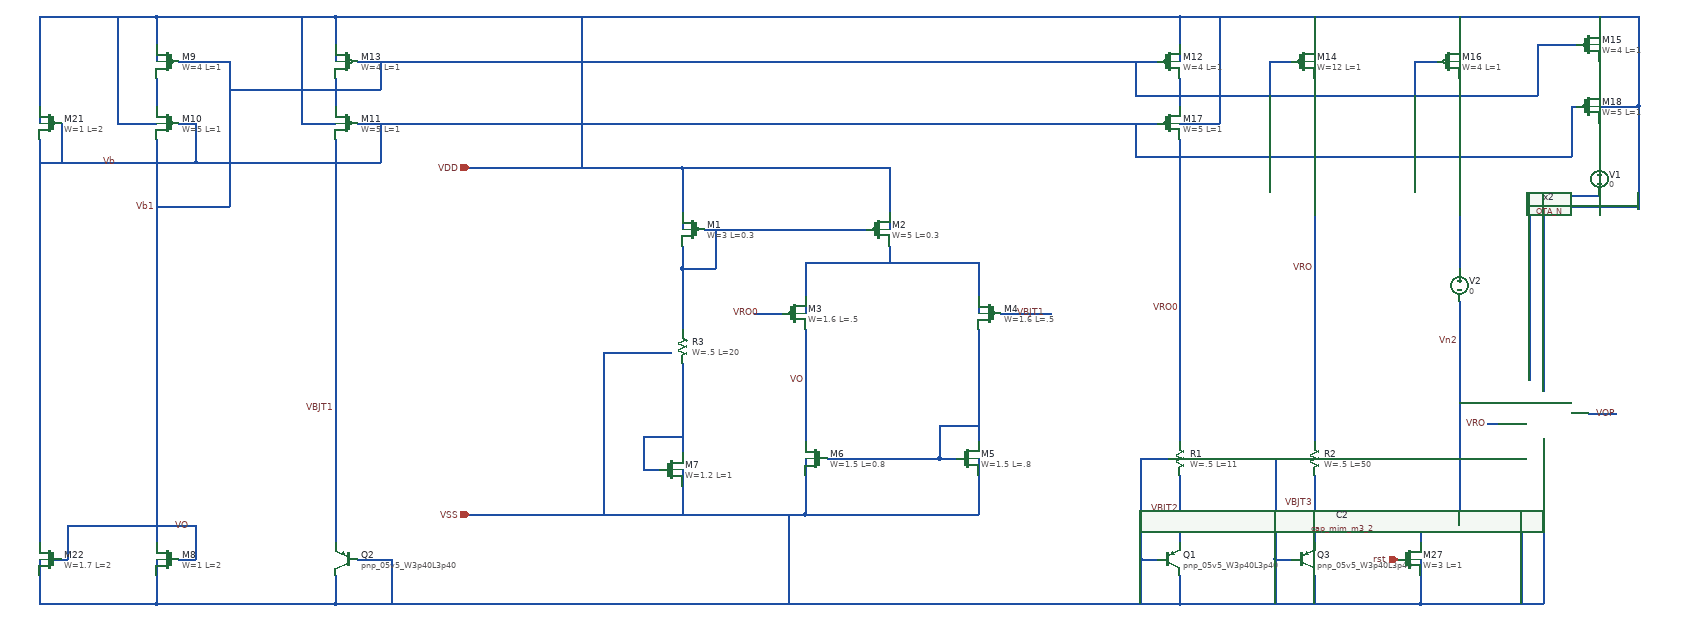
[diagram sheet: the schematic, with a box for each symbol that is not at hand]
v {xschem version=3.4.4 file_version=1.2
}
G {}
K {}
V {}
S {}
E {}
N 2615 -717.5 2615 -597.5 {
lab=VBJT2}
N 1145 -1457.5 2575 -1457.5 {
lab=Vb1}
N 1105 -1537.5 1105 -1487.5 {
lab=VDD}
N 1105 -1537.5 2615 -1537.5 {
lab=VDD}
N 2615 -1537.5 2615 -1487.5 {
lab=VDD}
N 2615 -1487.5 2615 -1457.5 {
lab=VDD}
N 1105 -1487.5 1105 -1457.5 {
lab=VDD}
N 1105 -537.5 1105 -487.5 {
lab=VSS}
N 1105 -487.5 2615 -487.5 {
lab=VSS}
N 2615 -537.5 2615 -487.5 {
lab=VSS}
N 2545 -567.5 2575 -567.5 {
lab=VSS}
N 2545 -567.5 2545 -487.5 {
lab=VSS}
N 1145 -567.5 1175 -567.5 {
lab=VSS}
N 2855 -717.5 2855 -597.5 {
lab=VBJT3}
N 2785 -567.5 2815 -567.5 {
lab=VSS}
N 2615 -1537.5 2955 -1537.5 {
lab=VDD}
N 2855 -1487.5 2855 -1457.5 {
lab=VDD}
N 2855 -1327.5 2855 -797.5 {
lab=VRO}
N 2855 -797.5 2855 -777.5 {
lab=VRO}
N 2615 -487.5 2955 -487.5 {
lab=VSS}
N 2855 -537.5 2855 -487.5 {
lab=VSS}
N 2785 -567.5 2785 -487.5 {
lab=VSS}
N 2955 -1537.5 3225 -1537.5 {
lab=VDD}
N 3115 -1517.5 3115 -1487.5 {
lab=VDD}
N 3115 -1537.5 3115 -1517.5 {
lab=VDD}
N 1945 -1097.5 1945 -1037.5 {
lab=#net1}
N 1945 -1097.5 2255 -1097.5 {
lab=#net1}
N 2255 -1097.5 2255 -1037.5 {
lab=#net1}
N 2255 -977.5 2255 -777.5 {
lab=#net2}
N 1945 -977.5 1945 -777.5 {
lab=VO}
N 1985 -747.5 2015 -747.5 {
lab=#net2}
N 2185 -747.5 2215 -747.5 {
lab=#net2}
N 2185 -807.5 2185 -747.5 {
lab=#net2}
N 2185 -807.5 2255 -807.5 {
lab=#net2}
N 1945 -717.5 1945 -647.5 {
lab=VSS}
N 1945 -647.5 2255 -647.5 {
lab=VSS}
N 2255 -717.5 2255 -647.5 {
lab=VSS}
N 1945 -747.5 1945 -717.5 {
lab=VSS}
N 2255 -747.5 2255 -717.5 {
lab=VSS}
N 2255 -1037.5 2255 -1007.5 {
lab=#net1}
N 1945 -1037.5 1945 -1007.5 {
lab=#net1}
N 2095 -1187.5 2095 -1157.5 {
lab=VDD}
N 2095 -1127.5 2095 -1097.5 {
lab=#net1}
N 1725 -1187.5 1725 -1157.5 {
lab=VDD}
N 1725 -1127.5 1725 -1087.5 {
lab=#net3}
N 1725 -1087.5 1785 -1087.5 {
lab=#net3}
N 1785 -1157.5 1785 -1087.5 {
lab=#net3}
N 1765 -1157.5 2055 -1157.5 {
lab=#net3}
N 1545 -647.5 1945 -647.5 {
lab=VSS}
N 1725 -1267.5 2095 -1267.5 {
lab=VDD}
N 1345 -647.5 1545 -647.5 {
lab=VSS}
N 1725 -1087.5 1725 -1027.5 {
lab=#net3}
N 1725 -1027.5 1725 -1017.5 {
lab=#net3}
N 1545 -1537.5 1545 -1367.5 {
lab=VDD}
N 1915 -647.5 1915 -487.5 {
lab=VSS}
N 2015 -747.5 2185 -747.5 {
lab=#net2}
N 1655 -727.5 1685 -727.5 {
lab=#net4}
N 1655 -787.5 1655 -727.5 {
lab=#net4}
N 1655 -787.5 1725 -787.5 {
lab=#net4}
N 1725 -727.5 1725 -697.5 {
lab=VSS}
N 1725 -917.5 1725 -757.5 {
lab=#net4}
N 1725 -697.5 1725 -647.5 {
lab=VSS}
N 1725 -1017.5 1725 -977.5 {
lab=#net3}
N 2295 -1007.5 2385 -1007.5 {
lab=VBJT1}
N 1855 -1007.5 1905 -1007.5 {
lab=VRO0}
N 825 -567.5 855 -567.5 {
lab=VO}
N 855 -627.5 855 -567.5 {
lab=VO}
N 785 -567.5 785 -537.5 {
lab=VSS}
N 785 -537.5 785 -487.5 {
lab=VSS}
N 785 -487.5 1105 -487.5 {
lab=VSS}
N 785 -1537.5 785 -1487.5 {
lab=VDD}
N 785 -1487.5 785 -1457.5 {
lab=VDD}
N 785 -1427.5 785 -1377.5 {
lab=#net5}
N 1345 -1267.5 1725 -1267.5 {
lab=VDD}
N 1545 -1367.5 1545 -1267.5 {
lab=VDD}
N 855 -1347.5 855 -1277.5 {
lab=Vb}
N 825 -1347.5 855 -1347.5 {
lab=Vb}
N 825 -1457.5 855 -1457.5 {
lab=Vb1}
N 785 -1537.5 1105 -1537.5 {
lab=VDD}
N 1105 -1427.5 1105 -1377.5 {
lab=#net6}
N 2615 -1427.5 2615 -1377.5 {
lab=#net7}
N 2855 -1437.5 2855 -1387.5 {
lab=VRO}
N 2855 -1537.5 2855 -1487.5 {
lab=VDD}
N 2535 -1457.5 2535 -1397.5 {
lab=Vb1}
N 2535 -1397.5 2875 -1397.5 {
lab=Vb1}
N 2775 -1457.5 2775 -1397.5 {
lab=Vb1}
N 2775 -1457.5 2815 -1457.5 {
lab=Vb1}
N 1145 -1347.5 2575 -1347.5 {
lab=Vb}
N 2615 -1317.5 2615 -777.5 {
lab=VRO0}
N 1185 -1457.5 1185 -1407.5 {
lab=Vb1}
N 1185 -1347.5 1185 -1277.5 {
lab=Vb}
N 855 -1457.5 915 -1457.5 {
lab=Vb1}
N 915 -1457.5 915 -1197.5 {
lab=Vb1}
N 785 -1197.5 915 -1197.5 {
lab=Vb1}
N 2875 -1397.5 3145 -1397.5 {
lab=Vb1}
N 785 -1317.5 785 -1147.5 {
lab=Vb1}
N 785 -1097.5 785 -597.5 {
lab=Vb1}
N 1175 -567.5 1205 -567.5 {
lab=VSS}
N 1205 -507.5 1205 -487.5 {
lab=VSS}
N 1205 -567.5 1205 -517.5 {
lab=VSS}
N 1205 -517.5 1205 -507.5 {
lab=VSS}
N 1105 -677.5 1105 -597.5 {
lab=VBJT1}
N 1105 -837.5 1105 -737.5 {
lab=VBJT1}
N 1105 -1317.5 1105 -837.5 {
lab=VBJT1}
N 1105 -737.5 1105 -677.5 {
lab=VBJT1}
N 915 -1407.5 1185 -1407.5 {
lab=Vb1}
N 1725 -1267.5 1725 -1187.5 {
lab=VDD}
N 2095 -1267.5 2095 -1187.5 {
lab=VDD}
N 785 -1147.5 785 -1097.5 {
lab=Vb1}
N 575 -1377.5 575 -1347.5 {
lab=VDD}
N 575 -1277.5 855 -1277.5 {
lab=Vb}
N 575 -1537.5 575 -1377.5 {
lab=VDD}
N 575 -1537.5 785 -1537.5 {
lab=VDD}
N 625 -627.5 855 -627.5 {
lab=VO}
N 625 -627.5 625 -567.5 {
lab=VO}
N 595 -567.5 625 -567.5 {
lab=VO}
N 575 -1317.5 575 -627.5 {
lab=Vb}
N 615 -1347.5 615 -1277.5 {
lab=Vb}
N 855 -1277.5 1185 -1277.5 {
lab=Vb}
N 2855 -1387.5 2855 -1327.5 {
lab=VRO}
N 2795 -747.5 2835 -747.5 {
lab=VSS}
N 2785 -747.5 2785 -567.5 {
lab=VSS}
N 2785 -747.5 2795 -747.5 {
lab=VSS}
N 2545 -747.5 2545 -567.5 {
lab=VSS}
N 2545 -747.5 2595 -747.5 {
lab=VSS}
N 1585 -937.5 1705 -937.5 {
lab=VSS}
N 1585 -937.5 1585 -647.5 {
lab=VSS}
N 3365 -1517.5 3365 -1487.5 {
lab=VDD}
N 3365 -1457.5 3365 -1407.5 {
lab=#net8}
N 3255 -1487.5 3255 -1397.5 {
lab=Vb1}
N 3255 -1487.5 3325 -1487.5 {
lab=Vb1}
N 2535 -1347.5 2535 -1287.5 {
lab=Vb}
N 3315 -1377.5 3315 -1287.5 {
lab=Vb}
N 3315 -1377.5 3325 -1377.5 {
lab=Vb}
N 3365 -1537.5 3365 -1517.5 {
lab=VDD}
N 3365 -1347.5 3365 -1277.5 {
lab=#net9}
N 715 -1347.5 785 -1347.5 {
lab=VDD}
N 715 -1537.5 715 -1347.5 {
lab=VDD}
N 1045 -1347.5 1105 -1347.5 {
lab=VDD}
N 1045 -1537.5 1045 -1347.5 {
lab=VDD}
N 2615 -1347.5 2685 -1347.5 {
lab=VDD}
N 2685 -1537.5 2685 -1347.5 {
lab=VDD}
N 3365 -1377.5 3435 -1377.5 {
lab=VDD}
N 3435 -1537.5 3435 -1377.5 {
lab=VDD}
N 3165 -627.5 3225 -627.5 {
lab=VSS}
N 3045 -627.5 3045 -597.5 {
lab=VSS}
N 3045 -567.5 3045 -537.5 {
lab=VSS}
N 3115 -1387.5 3115 -1377.5 {
lab=#net10}
N 3115 -1317.5 3115 -1227.5 {
lab=#net10}
N 3115 -1377.5 3115 -1317.5 {
lab=#net10}
N 3045 -627.5 3085 -627.5 {
lab=VSS}
N 3225 -627.5 3225 -487.5 {
lab=VSS}
N 3125 -627.5 3155 -627.5 {
lab=VSS}
N 575 -627.5 575 -597.5 {
lab=Vb}
N 575 -537.5 575 -487.5 {
lab=VSS}
N 575 -567.5 575 -537.5 {
lab=VSS}
N 575 -487.5 785 -487.5 {
lab=VSS}
N 3115 -1427.5 3115 -1387.5 {
lab=#net10}
N 3035 -1457.5 3075 -1457.5 {
lab=Vb1}
N 3035 -1457.5 3035 -1397.5 {
lab=Vb1}
N 3075 -487.5 3155 -487.5 {
lab=VSS}
N 3115 -1227.5 3115 -1087.5 {
lab=#net10}
N 3115 -1027.5 3115 -807.5 {
lab=VSS}
N 2955 -487.5 3045 -487.5 {
lab=VSS}
N 3045 -487.5 3075 -487.5 {
lab=VSS}
N 3155 -627.5 3165 -627.5 {
lab=VSS}
N 2535 -1287.5 3315 -1287.5 {
lab=Vb}
N 3145 -1397.5 3255 -1397.5 {
lab=Vb1}
N 3225 -1537.5 3435 -1537.5 {
lab=VDD}
N 3085 -627.5 3125 -627.5 {
lab=VSS}
N 3155 -487.5 3195 -487.5 {
lab=VSS}
N 3045 -537.5 3045 -487.5 {
lab=VSS}
N 3265 -1057.5 3265 -877.5 {
lab=VDD}
N 3265 -777.5 3265 -487.5 {
lab=VSS}
N 3215 -487.5 3265 -487.5 {
lab=VSS}
N 3195 -487.5 3215 -487.5 {
lab=VSS}
N 3345 -827.5 3395 -827.5 {
lab=VOP}
N 3265 -782.5 3265 -777.5 {
lab=VSS}
N 3115 -807.5 3115 -627.5 {
lab=VSS}
N 3265 -877.5 3265 -867.5 {
lab=VDD}
N 3240 -1217.5 3240 -887.5 {
lab=#net11}
N 3240 -1217.5 3365 -1217.5 {
lab=#net11}
N 3265 -1197.5 3265 -1057.5 {
lab=VDD}
N 3265 -1197.5 3435 -1197.5 {
lab=VDD}
N 3435 -1377.5 3435 -1192.5 {
lab=VDD}
N 3115 -847.5 3185 -847.5 {
lab=VSS}
N 3165 -810 3185 -810 {
lab=#net12}
C {sky130_fd_pr/pnp_05v5.sym} 2595 -567.5 0 0 {name=Q1
model=pnp_05v5_W3p40L3p40
m=6
spiceprefix=X
}
C {sky130_fd_pr/pnp_05v5.sym} 1125 -567.5 0 1 {name=Q2
model=pnp_05v5_W3p40L3p40
m=1
spiceprefix=X
}
C {sky130_fd_pr/pfet_01v8.sym} 2595 -1457.5 0 0 {name=M12
L=1
W=4
nf=2
mult=1
ad="'int((nf+1)/2) * W/nf * 0.29'" 
pd="'2*int((nf+1)/2) * (W/nf + 0.29)'"
as="'int((nf+2)/2) * W/nf * 0.29'" 
ps="'2*int((nf+2)/2) * (W/nf + 0.29)'"
nrd="'0.29 / W'" nrs="'0.29 / W'"
sa=0 sb=0 sd=0
model=pfet_01v8
spiceprefix=X
}
C {sky130_fd_pr/pfet_01v8.sym} 1125 -1457.5 0 1 {name=M13
L=1
W=4
nf=2
mult=1
ad="'int((nf+1)/2) * W/nf * 0.29'" 
pd="'2*int((nf+1)/2) * (W/nf + 0.29)'"
as="'int((nf+2)/2) * W/nf * 0.29'" 
ps="'2*int((nf+2)/2) * (W/nf + 0.29)'"
nrd="'0.29 / W'" nrs="'0.29 / W'"
sa=0 sb=0 sd=0
model=pfet_01v8
spiceprefix=X
}
C {sky130_fd_pr/pfet_01v8.sym} 2835 -1457.5 0 0 {name=M14
L=1
W=12
nf=2
mult=1
ad="'int((nf+1)/2) * W/nf * 0.29'" 
pd="'2*int((nf+1)/2) * (W/nf + 0.29)'"
as="'int((nf+2)/2) * W/nf * 0.29'" 
ps="'2*int((nf+2)/2) * (W/nf + 0.29)'"
nrd="'0.29 / W'" nrs="'0.29 / W'"
sa=0 sb=0 sd=0
model=pfet_01v8
spiceprefix=X
}
C {sky130_fd_pr/pnp_05v5.sym} 2835 -567.5 0 0 {name=Q3
model=pnp_05v5_W3p40L3p40
m=1
spiceprefix=X
}
C {devices/lab_wire.sym} 2855 -1087.5 0 0 {name=p6 sig_type=std_logic lab=VRO}
C {devices/lab_wire.sym} 2615 -657.5 0 0 {name=p7 sig_type=std_logic lab=VBJT2}
C {devices/lab_wire.sym} 2855 -667.5 0 0 {name=p8 sig_type=std_logic lab=VBJT3}
C {sky130_fd_pr/pfet_01v8.sym} 3095 -1457.5 0 0 {name=M16
L=1
W=4
nf=2
mult=1
ad="'int((nf+1)/2) * W/nf * 0.29'" 
pd="'2*int((nf+1)/2) * (W/nf + 0.29)'"
as="'int((nf+2)/2) * W/nf * 0.29'" 
ps="'2*int((nf+2)/2) * (W/nf + 0.29)'"
nrd="'0.29 / W'" nrs="'0.29 / W'"
sa=0 sb=0 sd=0
model=pfet_01v8
spiceprefix=X
}
C {devices/lab_wire.sym} 1105 -837.5 0 0 {name=p4 sig_type=std_logic lab=VBJT1}
C {sky130_fd_pr/pfet_01v8.sym} 1745 -1157.5 0 1 {name=M1
L=0.3
W=3
nf=2
mult=1
ad="'int((nf+1)/2) * W/nf * 0.29'" 
pd="'2*int((nf+1)/2) * (W/nf + 0.29)'"
as="'int((nf+2)/2) * W/nf * 0.29'" 
ps="'2*int((nf+2)/2) * (W/nf + 0.29)'"
nrd="'0.29 / W'" nrs="'0.29 / W'"
sa=0 sb=0 sd=0
model=pfet_01v8
spiceprefix=X
}
C {sky130_fd_pr/pfet_01v8.sym} 2075 -1157.5 0 0 {name=M2
L=0.3
W=5
nf=2
mult=1
ad="'int((nf+1)/2) * W/nf * 0.29'" 
pd="'2*int((nf+1)/2) * (W/nf + 0.29)'"
as="'int((nf+2)/2) * W/nf * 0.29'" 
ps="'2*int((nf+2)/2) * (W/nf + 0.29)'"
nrd="'0.29 / W'" nrs="'0.29 / W'"
sa=0 sb=0 sd=0
model=pfet_01v8
spiceprefix=X
}
C {sky130_fd_pr/pfet_01v8.sym} 1925 -1007.5 0 0 {name=M3
L=.5
W=1.6
nf=2
mult=1
ad="'int((nf+1)/2) * W/nf * 0.29'" 
pd="'2*int((nf+1)/2) * (W/nf + 0.29)'"
as="'int((nf+2)/2) * W/nf * 0.29'" 
ps="'2*int((nf+2)/2) * (W/nf + 0.29)'"
nrd="'0.29 / W'" nrs="'0.29 / W'"
sa=0 sb=0 sd=0
model=pfet_01v8
spiceprefix=X
}
C {sky130_fd_pr/pfet_01v8.sym} 2275 -1007.5 0 1 {name=M4
L=.5
W=1.6
nf=2
mult=1
ad="'int((nf+1)/2) * W/nf * 0.29'" 
pd="'2*int((nf+1)/2) * (W/nf + 0.29)'"
as="'int((nf+2)/2) * W/nf * 0.29'" 
ps="'2*int((nf+2)/2) * (W/nf + 0.29)'"
nrd="'0.29 / W'" nrs="'0.29 / W'"
sa=0 sb=0 sd=0
model=pfet_01v8
spiceprefix=X
}
C {sky130_fd_pr/nfet_01v8.sym} 2235 -747.5 0 0 {name=M5
L=.8
W=1.5
nf=2 
mult=1
ad="'int((nf+1)/2) * W/nf * 0.29'" 
pd="'2*int((nf+1)/2) * (W/nf + 0.29)'"
as="'int((nf+2)/2) * W/nf * 0.29'" 
ps="'2*int((nf+2)/2) * (W/nf + 0.29)'"
nrd="'0.29 / W'" nrs="'0.29 / W'"
sa=0 sb=0 sd=0
model=nfet_01v8
spiceprefix=X
}
C {sky130_fd_pr/nfet_01v8.sym} 1965 -747.5 0 1 {name=M6
L=0.8
W=1.5
nf=2 
mult=1
ad="'int((nf+1)/2) * W/nf * 0.29'" 
pd="'2*int((nf+1)/2) * (W/nf + 0.29)'"
as="'int((nf+2)/2) * W/nf * 0.29'" 
ps="'2*int((nf+2)/2) * (W/nf + 0.29)'"
nrd="'0.29 / W'" nrs="'0.29 / W'"
sa=0 sb=0 sd=0
model=nfet_01v8
spiceprefix=X
}
C {devices/ipin.sym} 1345 -1267.5 0 0 {name=p5 lab=VDD}
C {devices/ipin.sym} 1345 -647.5 0 0 {name=p9 lab=VSS}
C {devices/lab_wire.sym} 2615 -1017.5 0 0 {name=p1 sig_type=std_logic lab=VRO0}
C {devices/lab_wire.sym} 1945 -887.5 0 0 {name=p2 sig_type=std_logic lab=VO}
C {sky130_fd_pr/res_high_po.sym} 2855 -747.5 0 0 {name=R2
W=.5
L=50
model=res_high_po
spiceprefix=X
mult=1}
C {sky130_fd_pr/res_high_po.sym} 2615 -747.5 0 0 {name=R1
W=.5
L=11
model=res_high_po
spiceprefix=X
mult=1}
C {sky130_fd_pr/nfet_01v8.sym} 1705 -727.5 0 0 {name=M7
L=1
W=1.2
nf=2 
mult=1
ad="'int((nf+1)/2) * W/nf * 0.29'" 
pd="'2*int((nf+1)/2) * (W/nf + 0.29)'"
as="'int((nf+2)/2) * W/nf * 0.29'" 
ps="'2*int((nf+2)/2) * (W/nf + 0.29)'"
nrd="'0.29 / W'" nrs="'0.29 / W'"
sa=0 sb=0 sd=0
model=nfet_01v8
spiceprefix=X
}
C {sky130_fd_pr/res_high_po.sym} 1725 -947.5 0 0 {name=R3
W=.5
L=20
model=res_high_po
spiceprefix=X
mult=1}
C {devices/lab_wire.sym} 1865 -1007.5 0 0 {name=p3 sig_type=std_logic lab=VRO0}
C {devices/lab_wire.sym} 2375 -1007.5 0 0 {name=p10 sig_type=std_logic lab=VBJT1}
C {sky130_fd_pr/nfet_01v8.sym} 805 -567.5 0 1 {name=M8
L=2
W=1
nf=2 
mult=1
ad="'int((nf+1)/2) * W/nf * 0.29'" 
pd="'2*int((nf+1)/2) * (W/nf + 0.29)'"
as="'int((nf+2)/2) * W/nf * 0.29'" 
ps="'2*int((nf+2)/2) * (W/nf + 0.29)'"
nrd="'0.29 / W'" nrs="'0.29 / W'"
sa=0 sb=0 sd=0
model=nfet_01v8
spiceprefix=X
}
C {sky130_fd_pr/pfet_01v8.sym} 805 -1457.5 0 1 {name=M9
L=1
W=4
nf=2
mult=1
ad="'int((nf+1)/2) * W/nf * 0.29'" 
pd="'2*int((nf+1)/2) * (W/nf + 0.29)'"
as="'int((nf+2)/2) * W/nf * 0.29'" 
ps="'2*int((nf+2)/2) * (W/nf + 0.29)'"
nrd="'0.29 / W'" nrs="'0.29 / W'"
sa=0 sb=0 sd=0
model=pfet_01v8
spiceprefix=X
}
C {sky130_fd_pr/pfet_01v8.sym} 805 -1347.5 0 1 {name=M10
L=1
W=5
nf=2
mult=1
ad="'int((nf+1)/2) * W/nf * 0.29'" 
pd="'2*int((nf+1)/2) * (W/nf + 0.29)'"
as="'int((nf+2)/2) * W/nf * 0.29'" 
ps="'2*int((nf+2)/2) * (W/nf + 0.29)'"
nrd="'0.29 / W'" nrs="'0.29 / W'"
sa=0 sb=0 sd=0
model=pfet_01v8
spiceprefix=X
}
C {sky130_fd_pr/pfet_01v8.sym} 1125 -1347.5 0 1 {name=M11
L=1
W=5
nf=2
mult=1
ad="'int((nf+1)/2) * W/nf * 0.29'" 
pd="'2*int((nf+1)/2) * (W/nf + 0.29)'"
as="'int((nf+2)/2) * W/nf * 0.29'" 
ps="'2*int((nf+2)/2) * (W/nf + 0.29)'"
nrd="'0.29 / W'" nrs="'0.29 / W'"
sa=0 sb=0 sd=0
model=pfet_01v8
spiceprefix=X
}
C {sky130_fd_pr/pfet_01v8.sym} 2595 -1347.5 0 0 {name=M17
L=1
W=5
nf=2
mult=1
ad="'int((nf+1)/2) * W/nf * 0.29'" 
pd="'2*int((nf+1)/2) * (W/nf + 0.29)'"
as="'int((nf+2)/2) * W/nf * 0.29'" 
ps="'2*int((nf+2)/2) * (W/nf + 0.29)'"
nrd="'0.29 / W'" nrs="'0.29 / W'"
sa=0 sb=0 sd=0
model=pfet_01v8
spiceprefix=X
}
C {devices/lab_wire.sym} 715 -1277.5 0 0 {name=p12 sig_type=std_logic lab=Vb}
C {devices/lab_wire.sym} 785 -1197.5 0 0 {name=p13 sig_type=std_logic lab=Vb1}
C {sky130_fd_pr/pfet_01v8.sym} 595 -1347.5 0 1 {name=M21
L=2
W=1
nf=2
mult=1
ad="'int((nf+1)/2) * W/nf * 0.29'" 
pd="'2*int((nf+1)/2) * (W/nf + 0.29)'"
as="'int((nf+2)/2) * W/nf * 0.29'" 
ps="'2*int((nf+2)/2) * (W/nf + 0.29)'"
nrd="'0.29 / W'" nrs="'0.29 / W'"
sa=0 sb=0 sd=0
model=pfet_01v8
spiceprefix=X
}
C {sky130_fd_pr/nfet_01v8.sym} 595 -567.5 0 1 {name=M22
L=2
W=1.7
nf=2 
mult=1
ad="'int((nf+1)/2) * W/nf * 0.29'" 
pd="'2*int((nf+1)/2) * (W/nf + 0.29)'"
as="'int((nf+2)/2) * W/nf * 0.29'" 
ps="'2*int((nf+2)/2) * (W/nf + 0.29)'"
nrd="'0.29 / W'" nrs="'0.29 / W'"
sa=0 sb=0 sd=0
model=nfet_01v8
spiceprefix=X
}
C {devices/lab_wire.sym} 845 -627.5 0 0 {name=p11 sig_type=std_logic lab=VO}
C {devices/lab_wire.sym} 3115 -957.5 0 0 {name=p16 sig_type=std_logic lab=Vn2}
C {devices/ipin.sym} 3005 -567.5 0 0 {name=p20 lab=rst}
C {sky130_fd_pr/nfet_01v8.sym} 3025 -567.5 0 0 {name=M27
L=1
W=3
nf=2 
mult=1
ad="'int((nf+1)/2) * W/nf * 0.29'" 
pd="'2*int((nf+1)/2) * (W/nf + 0.29)'"
as="'int((nf+2)/2) * W/nf * 0.29'" 
ps="'2*int((nf+2)/2) * (W/nf + 0.29)'"
nrd="'0.29 / W'" nrs="'0.29 / W'"
sa=0 sb=0 sd=0
model=nfet_01v8
spiceprefix=X
}
C {devices/lab_wire.sym} 3395 -827.5 0 0 {name=p15 sig_type=std_logic lab=VOP}
C {CNR_GR02_SKY130NM/OTA_N.sym} 3155 -967.5 0 0 {name=x2}
C {sky130_fd_pr/pfet_01v8.sym} 3345 -1487.5 0 0 {name=M15
L=1
W=4
nf=2
mult=1
ad="'int((nf+1)/2) * W/nf * 0.29'" 
pd="'2*int((nf+1)/2) * (W/nf + 0.29)'"
as="'int((nf+2)/2) * W/nf * 0.29'" 
ps="'2*int((nf+2)/2) * (W/nf + 0.29)'"
nrd="'0.29 / W'" nrs="'0.29 / W'"
sa=0 sb=0 sd=0
model=pfet_01v8
spiceprefix=X
}
C {sky130_fd_pr/pfet_01v8.sym} 3345 -1377.5 0 0 {name=M18
L=1
W=5
nf=2
mult=1
ad="'int((nf+1)/2) * W/nf * 0.29'" 
pd="'2*int((nf+1)/2) * (W/nf + 0.29)'"
as="'int((nf+2)/2) * W/nf * 0.29'" 
ps="'2*int((nf+2)/2) * (W/nf + 0.29)'"
nrd="'0.29 / W'" nrs="'0.29 / W'"
sa=0 sb=0 sd=0
model=pfet_01v8
spiceprefix=X
}
C {devices/lab_wire.sym} 3165 -810 0 0 {name=p17 sig_type=std_logic lab=VRO}
C {devices/vsource.sym} 3365 -1247.5 0 0 {name=V1 value=0 savecurrent=true}
C {devices/vsource.sym} 3115 -1057.5 0 0 {name=V2 value=0 savecurrent=true}
C {sky130_fd_pr/cap_mim_m3_2.sym} 3225 -577.5 0 1 {name=C2 model=cap_mim_m3_2 W=60 L=60 MF=1 spiceprefix=X}
